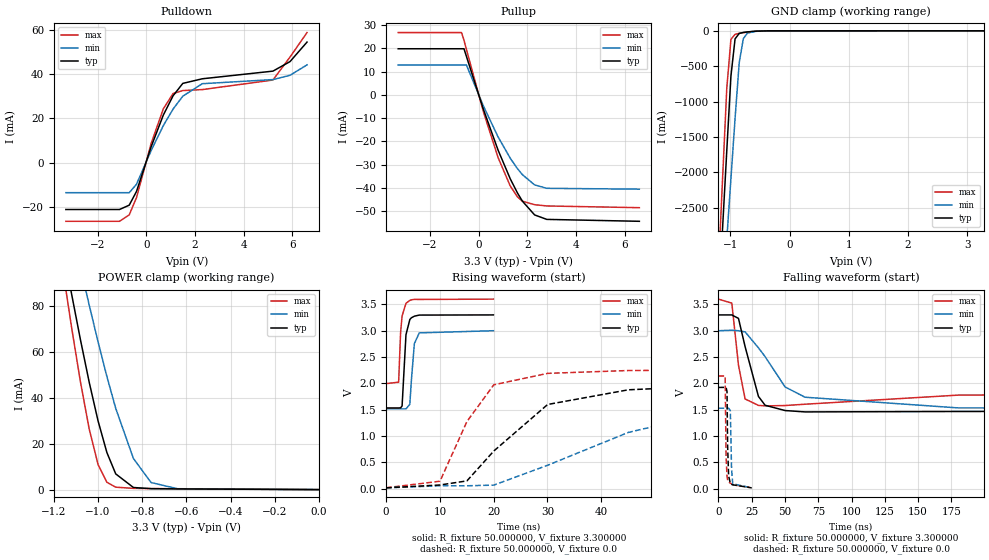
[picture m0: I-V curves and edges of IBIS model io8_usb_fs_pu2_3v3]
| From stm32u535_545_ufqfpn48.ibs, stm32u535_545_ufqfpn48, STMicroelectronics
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|   Model io8_usb_fs_pu2_3v3
[Model]  io8_usb_fs_pu2_3v3
Model_type I/O
Polarity   Non-Inverting
Enable   Active-Low
Vinl =   0.990000V
Vinh =   2.310000V
Vmeas =  1.650000V
Cref =   50.000000pF
Rref =   100.000000M
Vref =   0.0V
C_comp   7.156600pF   7.055100pF   7.302500pF
[Temperature Range]   25.000000   0.140000k   -40.000000
[Pullup Reference]   3.300000V   3.000000V   3.600000V
[Pulldown Reference]   0.0V   0.0V   0.0V
[POWER Clamp Reference]   3.300000V   3.000000V   3.600000V
[GND Clamp Reference]   0.0V   0.0V   0.0V
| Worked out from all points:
|   slope of the pulldown table from 0 to 0.495 V, typ, clamps not added: 32.1 ohm
|   slope of the pullup table from 0 to 0.495 V, typ, clamps not added: 32.5 ohm
|   GND clamp passes 1 mA (typ) near -0.45 V on its own axis
|   POWER clamp passes 1 mA (typ) near -0.84 V on its own axis
|   rising waveform, R_fixture 50.000000, V_fixture 3.300000: 20-80 % time 535ps typ, 587ps min, 481ps max; typ from 1.53 V to 3.3 V
|   rising waveform, R_fixture 50.000000, V_fixture 0.0: 20-80 % time 12.1ns typ, 22.8ns min, 6.84ns max; typ from 0.015 V to 1.92 V
|   falling waveform, R_fixture 50.000000, V_fixture 3.300000: 20-80 % time 10.8ns typ, 27.1ns min, 4.19ns max; typ from 3.3 V to 1.53 V
|   falling waveform, R_fixture 50.000000, V_fixture 0.0: 20-80 % time 731ps typ, 738ps min, 647ps max; typ from 1.92 V to 0.015 V
[Pulldown]
|Voltage   I(typ)   I(min)   I(max)
-3.3V     -21.17mA   -13.57mA   -26.5mA
-1.1V     -21.17mA   -13.57mA   -26.5mA
-700mV    -19.21mA   -13.57mA   -23.62mA
-400mV    -13mA      -9.744mA   -15.76mA
200mV     7.194mA    5.463mA    8.657mA
700mV     21.5mA     16.74mA    24.31mA
1.1V      30.22mA    24.21mA    31.23mA
1.5V      35.83mA    30.05mA    32.59mA
2.3V      37.91mA    35.69mA    33.03mA
5.2V      41.37mA    37.55mA    37.35mA
5.9V      45.66mA    39.49mA    47.71mA
6.6V      54.5mA     44.2mA     58.8mA
[Pullup]
|Voltage   I(typ)   I(min)   I(max)
-3.3V     19.83mA    12.84mA    26.8mA
-700mV    19.83mA    12.84mA    26.8mA
-600mV    19.83mA    12.84mA    23.54mA
-500mV    16.56mA    12.84mA    19.54mA
200mV     -6.341mA   -4.864mA   -7.396mA
800mV     -23.81mA   -18.11mA   -27mA
1.3V      -36.16mA   -27.3mA    -39.23mA
1.6V      -42.32mA   -31.83mA   -43.97mA
1.8V      -45.79mA   -34.37mA   -45.78mA
2.3V      -51.69mA   -38.76mA   -47.29mA
2.8V      -53.61mA   -40.24mA   -47.83mA
6.6V      -54.43mA   -40.6mA    -48.57mA
[GND_clamp]
|Voltage   I(typ)   I(min)   I(max)
-3.3V     -9.287A    -9.833A    -9.745A
-1.2V     -3.857A    -4.664A    -3.345A
-1.13V    -2.774A    -3.805A    -2.072A
-1.06V    -1.695A    -2.947A    -813.1mA
-990mV    -641.8mA   -2.091A    -120.9mA
-920mV    -113.3mA   -1.238A    -49.89mA
-850mV    -36.8mA    -452mA     -36.31mA
-780mV    -22.65mA   -108.9mA   -26.22mA
-710mV    -15.23mA   -32.27mA   -17.43mA
-570mV    -5.119mA   -7.032mA   -4.907mA
-360mV    -90.45uA   -461.6uA   -25.95uA
3.28V     0A         40.32nA    -16.18nA
[POWER_clamp]
|Voltage   I(typ)   I(min)   I(max)
-3.28V    1.356A     1.167A     1.665A
-1.16V    106.4mA    132.1mA    96.52mA
-1.12V    85.6mA     114.5mA    71.06mA
-1.08V    65.66mA    97.31mA    47.29mA
-1.04V    46.92mA    80.61mA    26.47mA
-1V       30.05mA    64.57mA    10.98mA
-960mV    16.21mA    49.41mA    3.211mA
-920mV    6.863mA    35.49mA    1.059mA
-840mV    925uA      13.6mA     543.5uA
-760mV    407uA      3.079mA    463.6uA
-640mV    303.3uA    387.1uA    366.5uA
0V        0A         50.45nA    0A
[Ramp]
| variable   typ   min   max
dV/dt_r  1.14504/11.67560n   0.90742/22.84982n   1.27568/6.07880n
dV/dt_f  1.06014/10.04717n   0.89052/26.86162n   0.96306/3.79013n
R_load = 50.000000
[Rising Waveform]
R_fixture= 50.000000
V_fixture= 3.300000
V_fixture_min= 3.000000
V_fixture_max= 3.600000
|time   V(typ)   V(min)   V(max)
0s        1.533V     1.516V     1.995V
2.322ns   1.533V     1.516V     2.023V
2.683ns   1.535V     1.516V     2.965V
2.963ns   1.571V     1.516V     3.28V
3.684ns   2.923V     1.516V     3.52V
4.404ns   3.213V     1.603V     3.576V
4.685ns   3.245V     2.05V      3.586V
5.245ns   3.276V     2.756V     3.595V
6.166ns   3.297V     2.959V     3.594V
19.94ns   3.3V       3V         3.6V
[Rising Waveform]
R_fixture= 50.000000
V_fixture= 0.0
V_fixture_min= 0.0
V_fixture_max= 0.0
|time   V(typ)   V(min)   V(max)
0s        15.5mV     15.43mV    17.27mV
10.01ns   70.02mV    55.11mV    141.5mV
15.02ns   147.9mV    55.05mV    1.275V
20.02ns   715.6mV    67.32mV    1.973V
30.03ns   1.599V     444.9mV    2.19V
45.05ns   1.878V     1.069V     2.244V
55.06ns   1.923V     1.308V     2.249V
70.07ns   1.948V     1.426V     2.25V
145.1ns   1.956V     1.522V     2.242V
2.492us   1.923V     1.528V     2.14V
[Falling Waveform]
R_fixture= 50.000000
V_fixture= 3.300000
V_fixture_min= 3.000000
V_fixture_max= 3.600000
|time   V(typ)   V(min)   V(max)
0s        3.3V       3V         3.6V
10.01ns   3.3V       3.009V     3.524V
15.02ns   3.234V     3V         2.345V
20.02ns   2.696V     2.977V     1.703V
30.03ns   1.752V     2.675V     1.582V
35.04ns   1.584V     2.507V     1.572V
50.05ns   1.484V     1.932V     1.579V
65.07ns   1.458V     1.737V     1.604V
180.2ns   1.466V     1.534V     1.777V
2.492us   1.533V     1.516V     1.995V
[Falling Waveform]
R_fixture= 50.000000
V_fixture= 0.0
V_fixture_min= 0.0
V_fixture_max= 0.0
|time   V(typ)   V(min)   V(max)
0s        1.923V     1.528V     2.14V
5.005ns   1.924V     1.528V     2.14V
5.706ns   1.924V     1.529V     596mV
6.406ns   1.845V     1.529V     238.6mV
6.857ns   813.9mV    1.529V     168.1mV
7.608ns   244mV      1.529V     127.2mV
8.909ns   99.86mV    1.48V      103.6mV
9.81ns    82.08mV    379.9mV    92.49mV
10.71ns   73.47mV    92.55mV    75.4mV
24.92ns   15.5mV     15.43mV    17.27mV
